VERSION 5.7 ;
DIVIDERCHAR "/" ;
BUSBITCHARS "[]" ;

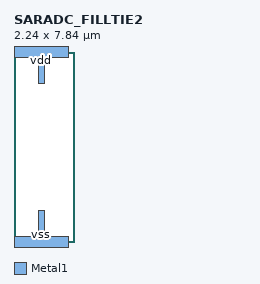
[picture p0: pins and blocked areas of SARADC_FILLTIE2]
MACRO SARADC_FILLTIE2
  CLASS BLOCK ;
  FOREIGN SARADC_FILLTIE2 ;
  ORIGIN 0.000 0.000 ;
  SIZE 2.240 BY 7.840 ;
  SYMMETRY X Y R90 ;
  PIN vdd
    DIRECTION INOUT ;
    USE POWER ;
    PORT
      LAYER Metal1 ;
        RECT 1.000 6.550 1.240 7.610 ;
        RECT 0.000 7.610 2.240 8.070 ;
    END
  END vdd
  PIN vss
    DIRECTION INOUT ;
    USE GROUND ;
    PORT
      LAYER Metal1 ;
        RECT 0.000 -0.230 2.240 0.230 ;
        RECT 1.000 0.230 1.240 1.290 ;
    END
  END vss
END SARADC_FILLTIE2

END LIBRARY
